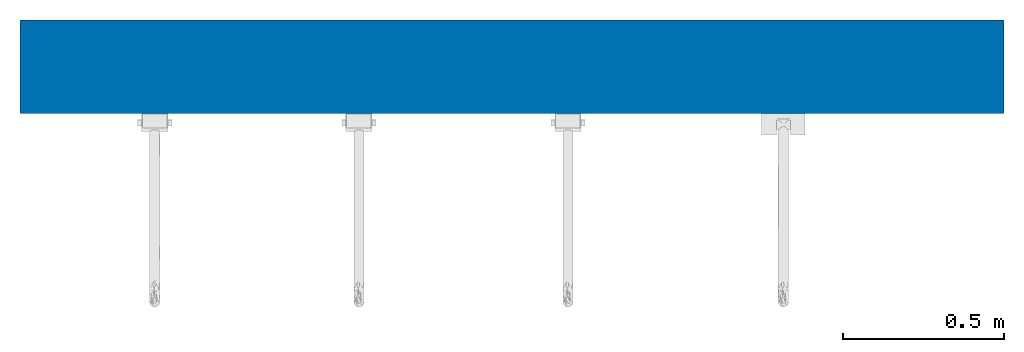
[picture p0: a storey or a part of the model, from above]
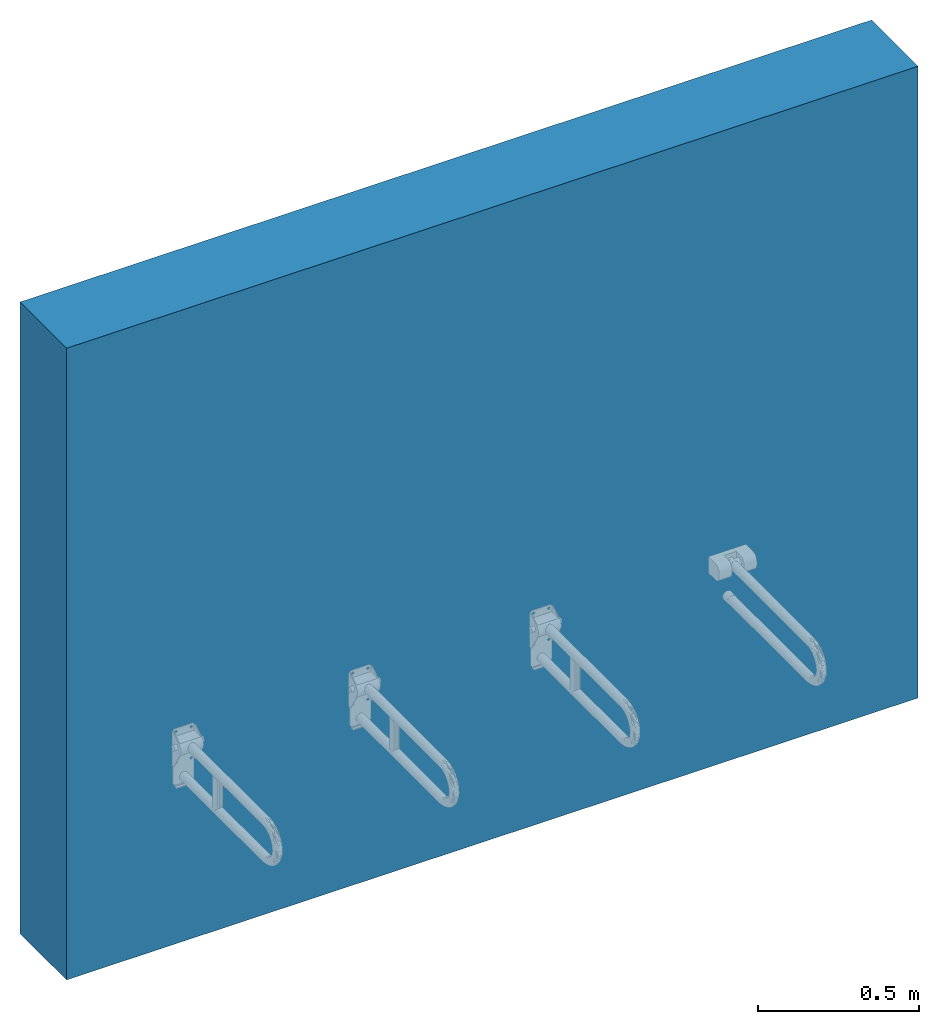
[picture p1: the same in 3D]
Properties of the parts of a building model (IFC2X3)

# File
Description: ViewDefinition [CoordinationView]
File name: Project Number
Time: 2018-10-12T06:44:37
Written by: The EXPRESS Data Manager Version 5.02.0100.07 : 28 Aug 2013
Made in: 20140606_1530(x64) - Exporter 2015.0.2014.0606 - Default UI
Comment: STEP Physical File produced by: The EXPRESS Data Manager Version 5.02.0100.07 : 28 Aug 2013 * Module: EDMstepFileFactory/EDMstandAlone * Creation date: Fri Oct 12 06:44:37 2018 * Host: SarahSams-HP * Database: C:\Users\SARAHS~1\AppData\Local\Temp\{1AB367D2-7B9F-4D54-B3BF-8B94C3EB91B9}\ifc * Database version: 5507 * Database creation date: Fri Oct 12 06:44:36 2018 * Schema: IFC2X3 * Model: DataRepository.ifc * Model creation date: Fri Oct 12 06:44:36 2018 * Header model: DataRepository.ifc_HeaderModel * Header model creation date: Fri Oct 12 06:44:36 2018 * EDMuser: sdai-user * EDMgroup: sdai-group * License ID and type: 5605 : Permanent license. Expiry date: * EDMstepFileFactory options: 020000

# IfcProject, Project Number
LongName: Project Name; Phase: Project Status

# IfcSite, Default
RefLatitude: 51, 30, 0, 549316; RefLongitude: 0, -7, -34, -450321; RefElevation: 0 mm
Other - Category: Project Information; Client Name: Owner; Project Address: Enter address here; Project Issue Date: Issue Date; Project Name: Project Name; Project Number: Project Number; Project Status: Project Status

# IfcBuilding
Pset_BuildingCommon - NumberOfStoreys: 1
Other - Category: Project Information; Client Name: Owner; Project Address: Enter address here; Project Issue Date: Issue Date; Project Name: Project Name; Project Number: Project Number; Project Status: Project Status

# IfcBuildingStorey, Level 0
LongName: Level 0; Elevation: 0 mm
Other - Category: Levels; Family Name: Level; Family: Level: Circle Head - Project Datum; Family and Type: Level: Circle Head - Project Datum; Type: Level: Circle Head - Project Datum; Type Id: Level: Circle Head - Project Datum
Identity Data - Type Name: Circle Head - Project Datum; Structural: no; Building Story: yes; Name: Level 0
Graphics - Color: 0; Line Pattern: Centre; Line Weight: 1; Symbol: Anno_Level_Head_Circle: Standard; Symbol at End 1 Default: yes; Symbol at End 2 Default: no
Constraints - Elevation Base: Project Base Point; Elevation: 0 mm
Dimensions - Computation Height: 0 mm

# IfcBuildingElementProxy: Brushed Stainless Steel, Duten_SStHandrls_B660:Brushed Stainless Steel:307409
In: Level 0
Classification: E2020200 Furniture & Accessories (Uniformat); Material: Duten_Metal_BrushedStainlessSteel
Pset_BuildingElementProxyCommon - Reference: n/a
Pset_ManufacturerTypeInformation - ModelReference: Brushed Stainless Steel; Manufacturer: Duten
Constraints - Elevation: 600 mm; Level: Level: Level 0; IsSteel: no; StainlessSteel: yes
Dimensions - Area: 0.138874 m2; Volume: 0.00137267 m3
Other - Category: Generic Models; Family: Duten_SStHandrls_B660: Brushed Stainless Steel; Family and Type: Duten_SStHandrls_B660: Brushed Stainless Steel; Host Id: Basic Wall: Wall-Ext_102Bwk-75Ins-100LBlk-12P; Type: Duten_SStHandrls_B660: Brushed Stainless Steel; Type Id: Duten_SStHandrls_B660: Brushed Stainless Steel; AccessibilityPerformance: n/a; AssetIdentifier: n/a; AssetType: Moveable; BarCode: n/a; CodePerformance: n/a; Color: Defined by Finish; Constituents: Stainless Steel Tube, Wall Fixing Point; DurationUnit: Years; ExpectedLife: 25; Family Name: Duten_SStHandrls_B660; Features: For Installation next to a WC; Finish: Brushed, Polished or White Stainless Steel. Vinyl also available; Grade: n/a; InstallationDate: 1900-12-31T23:59:59; Material: Stainless Steel or Steel for White Finish; ModelNumber: B660-S; ModelReference: Brushed Stainless Steel; Name: StainlessSteelHandrails_B660_Duten; ReplacementCost: 0; SerialNumber: n/a; Shape: Rectangle; Size: (H) 171mm x (L) 600mm x (W) 106.5mm; SustainabilityPerformance: n/a; TagNumber: n/a; WarrantyDescription: n/a; WarrantyDurationLabor: 25; WarrantyDurationParts: 25; WarrantyDurationUnit: Years; WarrantyGuarantorLabor: contact@duten.fr; WarrantyGuarantorParts: contact@duten.fr; WarrantyStartDate: 1900-12-31T23:59:59
Phasing - Phase Created: New Construction
General - Author: Diane Butterworth Ltd; ManufacturerName: Duten; ManufacturerURL: http://www.duten.fr/; NBSDescription: Stainless steel handrails; NBSReference: 45-70-70/480; ProductInformation: http://www.duten.fr/?post_type=produits&p=610&ca=barre-appui-siege-de-douche; Revision: n/a; Uniclass2015Code: Pr-Products v1.10; Uniclass2015Title: Stainless steel handrails; Uniclass2015Version: Pr_25_30_36_84
Identity Data - Assembly Code: E2020200; Assembly Description: Furniture & Accessories; Cost: 0; Description: Brushed Stainless Steel; Keynote: Pr_25_30_36_84; Manufacturer: Duten; Model: B660-S; Type Comments: Brushed Stainless Steel; Type Name: Brushed Stainless Steel; URL: http://www.duten.fr/
Materials and Finishes - HandrailFinish: Duten_Metal_BrushedStainlessSteel

# IfcBuildingElementProxy: Polished Stainless Steel, Duten_SStHandrls_B660:Polished Stainless Steel:307429
In: Level 0
Classification: E2020200 Furniture & Accessories (Uniformat); Material: Duten_Metal_PolishedStainlessSteel
Pset_BuildingElementProxyCommon - Reference: n/a
Pset_ManufacturerTypeInformation - ModelReference: Polished Stainless Steel; Manufacturer: Duten
Constraints - Elevation: 600 mm; Level: Level: Level 0; IsSteel: no; StainlessSteel: yes
Dimensions - Area: 0.138874 m2; Volume: 0.00137267 m3
Other - Category: Generic Models; Host Id: Basic Wall: Wall-Ext_102Bwk-75Ins-100LBlk-12P; Family: Duten_SStHandrls_B660: Polished Stainless Steel; Family and Type: Duten_SStHandrls_B660: Polished Stainless Steel; Type: Duten_SStHandrls_B660: Polished Stainless Steel; Type Id: Duten_SStHandrls_B660: Polished Stainless Steel; AccessibilityPerformance: n/a; AssetIdentifier: n/a; AssetType: Moveable; BarCode: n/a; CodePerformance: n/a; Color: Defined by Finish; Constituents: Stainless Steel Tube, Wall Fixing Point; DurationUnit: Years; ExpectedLife: 25; Family Name: Duten_SStHandrls_B660; Features: For Installation next to a WC; Finish: Brushed, Polished or White Stainless Steel. Vinyl also available; Grade: n/a; InstallationDate: 1900-12-31T23:59:59; Material: Stainless Steel or Steel for White Finish; ModelNumber: B660-B; ModelReference: Polished Stainless Steel; Name: StainlessSteelHandrails_B660_Duten; ReplacementCost: 0; SerialNumber: n/a; Shape: Rectangle; Size: (H) 171mm x (L) 600mm x (W) 106.5mm; SustainabilityPerformance: n/a; TagNumber: n/a; WarrantyDescription: n/a; WarrantyDurationLabor: 25; WarrantyDurationParts: 25; WarrantyDurationUnit: Years; WarrantyGuarantorLabor: contact@duten.fr; WarrantyGuarantorParts: contact@duten.fr; WarrantyStartDate: 1900-12-31T23:59:59
Phasing - Phase Created: New Construction
General - Author: Diane Butterworth Ltd; ManufacturerName: Duten; ManufacturerURL: http://www.duten.fr/; NBSDescription: Stainless steel handrails; NBSReference: 45-70-70/480; ProductInformation: http://www.duten.fr/?post_type=produits&p=610&ca=barre-appui-siege-de-douche; Revision: n/a; Uniclass2015Code: Pr-Products v1.10; Uniclass2015Title: Stainless steel handrails; Uniclass2015Version: Pr_25_30_36_84
Identity Data - Assembly Code: E2020200; Assembly Description: Furniture & Accessories; Cost: 0; Description: Polished Stainless Steel; Keynote: Pr_25_30_36_84; Manufacturer: Duten; Model: B660-B; Type Comments: Polished Stainless Steel; Type Name: Polished Stainless Steel; URL: http://www.duten.fr/
Materials and Finishes - HandrailFinish: Duten_Metal_PolishedStainlessSteel

# IfcBuildingElementProxy: Vinyl, Duten_SStHandrls_B660:Vinyl:307484
In: Level 0
Classification: E2020200 Furniture & Accessories (Uniformat); Material: Duten_Vinyl_Black
Pset_BuildingElementProxyCommon - Reference: n/a
Pset_ManufacturerTypeInformation - ModelReference: Vinyl; Manufacturer: Duten
Constraints - Level: Level: Level 0; Elevation: 600 mm; IsSteel: no; StainlessSteel: yes
Dimensions - Area: 0.138874 m2; Volume: 0.00137267 m3
Other - Category: Generic Models; Host Id: Basic Wall: Wall-Ext_102Bwk-75Ins-100LBlk-12P; Family: Duten_SStHandrls_B660: Vinyl; Family and Type: Duten_SStHandrls_B660: Vinyl; Type: Duten_SStHandrls_B660: Vinyl; Type Id: Duten_SStHandrls_B660: Vinyl; AccessibilityPerformance: n/a; AssetIdentifier: n/a; AssetType: Moveable; BarCode: n/a; CodePerformance: n/a; Color: Defined by Finish; Constituents: Stainless Steel Tube, Wall Fixing Point; DurationUnit: Years; ExpectedLife: 25; Family Name: Duten_SStHandrls_B660; Features: For Installation next to a WC; Finish: Brushed, Polished or White Stainless Steel. Vinyl also available; Grade: n/a; InstallationDate: 1900-12-31T23:59:59; Material: Stainless Steel or Steel for White Finish; ModelNumber: B660-V; ModelReference: Vinyl; Name: StainlessSteelHandrails_B660_Duten; ReplacementCost: 0; SerialNumber: n/a; Shape: Rectangle; Size: (H) 171mm x (L) 600mm x (W) 106.5mm; SustainabilityPerformance: n/a; TagNumber: n/a; WarrantyDescription: n/a; WarrantyDurationLabor: 25; WarrantyDurationParts: 25; WarrantyDurationUnit: Years; WarrantyGuarantorLabor: contact@duten.fr; WarrantyGuarantorParts: contact@duten.fr; WarrantyStartDate: 1900-12-31T23:59:59
Phasing - Phase Created: New Construction
General - Author: Diane Butterworth Ltd; ManufacturerName: Duten; ManufacturerURL: http://www.duten.fr/; NBSDescription: Stainless steel handrails; NBSReference: 45-70-70/480; ProductInformation: http://www.duten.fr/?post_type=produits&p=610&ca=barre-appui-siege-de-douche; Revision: n/a; Uniclass2015Code: Pr-Products v1.10; Uniclass2015Title: Stainless steel handrails; Uniclass2015Version: Pr_25_30_36_84
Identity Data - Assembly Code: E2020200; Assembly Description: Furniture & Accessories; Cost: 0; Description: Vinyl; Keynote: Pr_25_30_36_84; Manufacturer: Duten; Model: B660-V; Type Comments: Vinyl; Type Name: Vinyl; URL: http://www.duten.fr/
Materials and Finishes - HandrailFinish: Duten_Vinyl_Black

# IfcBuildingElementProxy: White Steel, Duten_SStHandrls_B660:White Steel:307523
In: Level 0
Classification: E2020200 Furniture & Accessories (Uniformat); Material: Duten_Metal_White
Other - AccessibilityPerformance: n/a; AssetIdentifier: n/a; AssetType: Moveable; BarCode: n/a; Category: Pr_25_30_36_84: Stainless steel handrails; CodePerformance: n/a; Color: Defined by Finish; Constituents: Stainless Steel Tube, Wall Fixing Point; DurationUnit: Years; ExpectedLife: 25; Family Name: Duten_SStHandrls_B660; Features: For Installation next to a WC; Finish: Brushed, Polished or White Stainless Steel. Vinyl also available; Grade: n/a; InstallationDate: 1900-12-31T23:59:59; Material: Stainless Steel or Steel for White Finish; ModelNumber: B660-W; ModelReference: White Steel; Name: StainlessSteelHandrails_B660_Duten; ReplacementCost: 0; SerialNumber: n/a; Shape: Rectangle; Size: (H) 171mm x (L) 600mm x (W) 135mm; SustainabilityPerformance: n/a; TagNumber: n/a; WarrantyDescription: n/a; WarrantyDurationLabor: 25; WarrantyDurationParts: 25; WarrantyDurationUnit: Years; WarrantyGuarantorLabor: contact@duten.fr; WarrantyGuarantorParts: contact@duten.fr; WarrantyStartDate: 1900-12-31T23:59:59; Host Id: Basic Wall: Wall-Ext_102Bwk-75Ins-100LBlk-12P; Family: Duten_SStHandrls_B660: White Steel; Family and Type: Duten_SStHandrls_B660: White Steel; Type: Duten_SStHandrls_B660: White Steel; Type Id: Duten_SStHandrls_B660: White Steel
Pset_BuildingElementProxyCommon - Reference: n/a
Pset_ManufacturerTypeInformation - ModelReference: White Steel; Manufacturer: Duten
Constraints - Level: Level: Level 0; Elevation: 600 mm; IsSteel: yes; StainlessSteel: no
Dimensions - Area: 0.138874 m2; Volume: 0.0014778 m3
Phasing - Phase Created: New Construction
General - Author: Diane Butterworth Ltd; ManufacturerName: Duten; ManufacturerURL: http://www.duten.fr/; NBSDescription: Stainless steel handrails; NBSReference: 45-70-70/480; ProductInformation: http://www.duten.fr/?post_type=produits&p=610&ca=barre-appui-siege-de-douche; Revision: n/a; Uniclass2015Code: Pr-Products v1.10; Uniclass2015Title: Stainless steel handrails; Uniclass2015Version: Pr_25_30_36_84
Identity Data - Assembly Code: E2020200; Assembly Description: Furniture & Accessories; Cost: 0; Description: White Steel; Keynote: Pr_25_30_36_84; Manufacturer: Duten; Model: B660-W; Type Comments: White Steel; Type Name: White Steel; URL: http://www.duten.fr/
Materials and Finishes - HandrailFinish: Duten_Metal_White

# IfcWallStandardCase: Basic Wall:Wall-Ext_102Bwk-75Ins-100LBlk-12P, Basic Wall:Wall-Ext_102Bwk-75Ins-100LBlk-12P:259702
In: Level 0
Type - PredefinedType: STANDARD; Material: Brick, Common 102.5 mm, Fiberglass Batt 75 mm, Concrete Masonry Units _Low Density 100 mm, Plaster 12.5 mm
Type - Analytical Properties - Absorptance: 0.7; Heat Transfer Coefficient (U): 0.235926; Roughness: 3; Thermal mass: 300303; Thermal Resistance (R): 4.23862
Type - Construction - Function: Exterior; Width: 290 mm; Wrapping at Inserts: Both
Type - Graphics - Coarse Scale Fill Color: 12632256; Coarse Scale Fill Pattern: Solid fill
Type - Identity Data - Keynote: F10; Type Name: Wall-Ext_102Bwk-75Ins-100LBlk-12P
Type - Materials and Finishes - Structural Material: Concrete Masonry Units _Low Density
Type - Other - Category: Walls; Family Name: Basic Wall
Constraints - Base Constraint: Level: Level 0; Base Extension Distance: 0 mm; Base is Attached: no; Base Offset: 0 mm; Location Line: Wall Centerline; Related to Mass: no; Room Bounding: yes; Top Extension Distance: 0 mm; Top is Attached: no; Top Offset: 0 mm; Unconnected Height: 2400 mm
Dimensions - Area: 7.344 m2; Length: 3060 mm; Volume: 2.12976 m3
Other - Family: Basic Wall: Wall-Ext_102Bwk-75Ins-100LBlk-12P; Family and Type: Basic Wall: Wall-Ext_102Bwk-75Ins-100LBlk-12P; Type: Basic Wall: Wall-Ext_102Bwk-75Ins-100LBlk-12P; Type Id: Basic Wall: Wall-Ext_102Bwk-75Ins-100LBlk-12P
Phasing - Phase Created: New Construction
Structural - Enable Analytical Model: no; Structural: no; Structural Usage: Non-bearing
Pset_WallCommon - Reference: Wall-Ext_102Bwk-75Ins-100LBlk-12P; LoadBearing: no; ExtendToStructure: no; IsExternal: yes; ThermalTransmittance: 0.235926 kg/K/s3
